VERSION 5.8 ;
BUSBITCHARS "<>" ;
DIVIDERCHAR "/" ;

UNITS
   DATABASE MICRONS 1000 ;
END UNITS

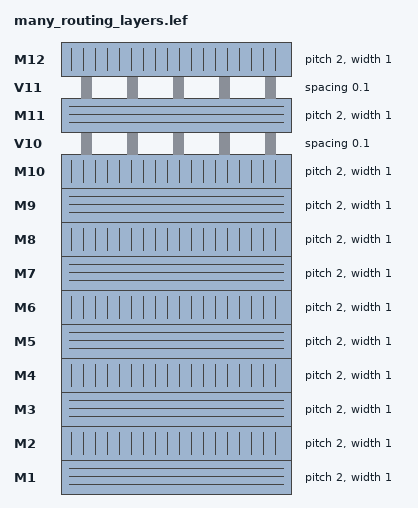
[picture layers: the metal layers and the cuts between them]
LAYER M1
   TYPE ROUTING ;
   WIDTH 1 ;
   PITCH 2 ;
   DIRECTION HORIZONTAL ;
END M1

LAYER M2
   TYPE ROUTING ;
   WIDTH 1 ;
   PITCH 2 ;
   DIRECTION VERTICAL ;
END M2

LAYER M3
   TYPE ROUTING ;
   WIDTH 1 ;
   PITCH 2 ;
   DIRECTION HORIZONTAL ;
END M3

LAYER M4
   TYPE ROUTING ;
   WIDTH 1 ;
   PITCH 2 ;
   DIRECTION VERTICAL ;
END M4

LAYER M5
   TYPE ROUTING ;
   WIDTH 1 ;
   PITCH 2 ;
   DIRECTION HORIZONTAL ;
END M5

LAYER M6
   TYPE ROUTING ;
   WIDTH 1 ;
   PITCH 2 ;
   DIRECTION VERTICAL ;
END M6

LAYER M7
   TYPE ROUTING ;
   WIDTH 1 ;
   PITCH 2 ;
   DIRECTION HORIZONTAL ;
END M7

LAYER M8
   TYPE ROUTING ;
   WIDTH 1 ;
   PITCH 2 ;
   DIRECTION VERTICAL ;
END M8

LAYER M9
   TYPE ROUTING ;
   WIDTH 1 ;
   PITCH 2 ;
   DIRECTION HORIZONTAL ;
END M9

LAYER M10
   TYPE ROUTING ;
   WIDTH 1 ;
   PITCH 2 ;
   DIRECTION VERTICAL ;
END M10

LAYER V10
   TYPE CUT ;
   SPACING 0.1 ;
END V10

LAYER M11
   TYPE ROUTING ;
   WIDTH 1 ;
   PITCH 2 ;
   DIRECTION HORIZONTAL ;
END M11

LAYER V11
   TYPE CUT ;
   SPACING 0.1 ;
END V11

LAYER M12
   TYPE ROUTING ;
   WIDTH 1 ;
   PITCH 2 ;
   DIRECTION VERTICAL ;
END M12
